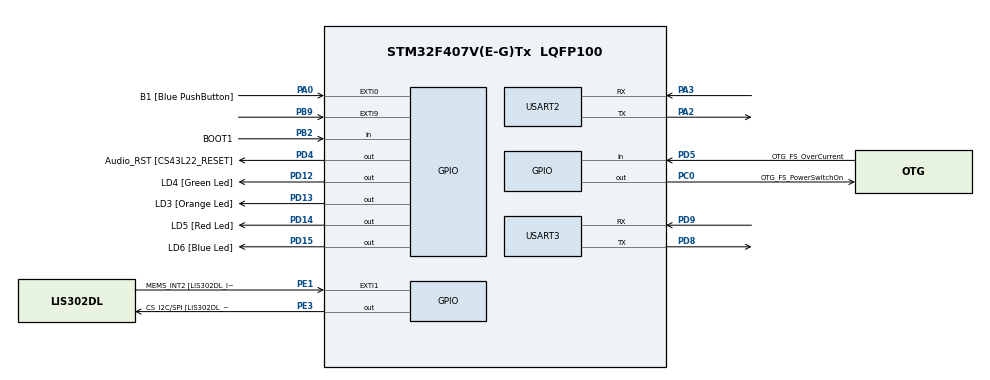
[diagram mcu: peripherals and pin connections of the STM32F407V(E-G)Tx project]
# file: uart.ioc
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Dma.Request0=USART2_RX
Dma.USART2_RX.0.Channel=DMA_CHANNEL_4
Dma.USART2_RX.0.Direction=DMA_PERIPH_TO_MEMORY
Dma.USART2_RX.0.FIFOMode=DMA_FIFOMODE_DISABLE
Dma.USART2_RX.0.FIFOThreshold=DMA_FIFO_THRESHOLD_HALFFULL
Dma.USART2_RX.0.Instance=DMA1_Stream5
Dma.USART2_RX.0.MemBurst=DMA_MBURST_SINGLE
Dma.USART2_RX.0.MemDataAlignment=DMA_MDATAALIGN_BYTE
Dma.USART2_RX.0.MemInc=DMA_MINC_DISABLE
Dma.USART2_RX.0.Mode=DMA_NORMAL
Dma.USART2_RX.0.PeriphBurst=DMA_PBURST_SINGLE
Dma.USART2_RX.0.PeriphDataAlignment=DMA_PDATAALIGN_BYTE
Dma.USART2_RX.0.PeriphInc=DMA_PINC_DISABLE
Dma.USART2_RX.0.Priority=DMA_PRIORITY_LOW
Mcu.Family=STM32F4
Mcu.Name=STM32F407V(E-G)Tx
Mcu.Package=LQFP100
NVIC.DMA1_Stream5_IRQn=true\:0\:0
NVIC.PriorityGroup=NVIC_PRIORITYGROUP_0
NVIC.USART2_IRQn=true\:0\:0
NVIC.USART3_IRQn=true\:0\:0
PA0-WKUP.GPIO_Label=B1 [Blue PushButton]
PA0-WKUP.GPIO_ModeDefaultEXTI=GPIO_MODE_EVT_RISING
PA0-WKUP.GPIO_PuPd=GPIO_NOPULL
PA0-WKUP.Signal=GPXTI0
PA10.GPIO_Label=OTG_FS_ID
PA10.GPIO_Mode=GPIO_MODE_AF_PP
PA10.GPIO_PuPd=GPIO_NOPULL
PA10.GPIO_Speed=GPIO_SPEED_LOW
PA10.Signal=USB_OTG_FS_ID
PA11.GPIO_Label=OTG_FS_DM
PA11.GPIO_Mode=GPIO_MODE_AF_PP
PA11.GPIO_PuPd=GPIO_NOPULL
PA11.GPIO_Speed=GPIO_SPEED_LOW
PA11.Signal=USB_OTG_FS_DM
PA12.GPIO_Label=OTG_FS_DP
PA12.GPIO_Mode=GPIO_MODE_AF_PP
PA12.GPIO_PuPd=GPIO_NOPULL
PA12.GPIO_Speed=GPIO_SPEED_LOW
PA12.Signal=USB_OTG_FS_DP
PA13.GPIO_Label=SWDIO
PA13.Mode=Trace-Asynchronous_SW
PA13.Signal=SYS_JTMS-SWDIO
PA14.GPIO_Label=SWCLK
PA14.Mode=Trace-Asynchronous_SW
PA14.Signal=SYS_JTCK-SWCLK
PA2.Mode=Asynchronous
PA2.Signal=USART2_TX
PA3.Mode=Asynchronous
PA3.Signal=USART2_RX
PA4.GPIO_Label=I2S3_WS [CS43L22_LRCK]
PA4.GPIO_Mode=GPIO_MODE_AF_PP
PA4.GPIO_PuPd=GPIO_NOPULL
PA4.GPIO_Speed=GPIO_SPEED_LOW
PA4.Signal=I2S3_WS
PA5.GPIO_Label=SPI1_SCK [LIS302DL_SCL/SPC]
PA5.GPIO_Mode=GPIO_MODE_AF_PP
PA5.GPIO_PuPd=GPIO_NOPULL
PA5.GPIO_Speed=GPIO_SPEED_LOW
PA5.Signal=SPI1_SCK
PA6.GPIO_Label=SPI1_MISO [LIS302DL_SDO]
PA6.GPIO_Mode=GPIO_MODE_AF_PP
PA6.GPIO_PuPd=GPIO_NOPULL
PA6.GPIO_Speed=GPIO_SPEED_LOW
PA6.Signal=SPI1_MISO
PA7.GPIO_Label=SPI1_MOSI [LIS302DL_SDA/SDI/SDO]
PA7.GPIO_Mode=GPIO_MODE_AF_PP
PA7.GPIO_PuPd=GPIO_NOPULL
PA7.GPIO_Speed=GPIO_SPEED_LOW
PA7.Signal=SPI1_MOSI
PA9.GPIO_Label=VBUS_FS
PA9.GPIO_Mode=GPIO_MODE_INPUT
PA9.GPIO_PuPd=GPIO_NOPULL
PA9.Signal=USB_OTG_FS_VBUS
PB10.GPIO_Label=CLK_IN [MP45DT02_CLK]
PB10.GPIO_Mode=GPIO_MODE_AF_PP
PB10.GPIO_PuPd=GPIO_NOPULL
PB10.GPIO_Speed=GPIO_SPEED_LOW
PB10.Signal=I2S2_CK
PB2.GPIO_Label=BOOT1
PB2.GPIO_Mode=GPIO_MODE_INPUT
PB2.GPIO_PuPd=GPIO_NOPULL
PB2.Signal=GPIO_Input
PB3.GPIO_Label=SWO
PB3.Mode=Trace-Asynchronous_SW
PB3.Signal=SYS_JTDO-SWO
PB6.GPIO_Label=Audio_SCL [CS43L22_SCL]
PB6.GPIO_Mode=GPIO_MODE_AF_OD
PB6.GPIO_PuPd=GPIO_NOPULL
PB6.GPIO_Speed=GPIO_SPEED_LOW
PB6.Signal=I2C1_SCL
PB9.Signal=GPXTI9
PC0.GPIO_Label=OTG_FS_PowerSwitchOn
PC0.GPIO_ModeDefaultOutputPP=GPIO_MODE_OUTPUT_PP
PC0.GPIO_PuPd=GPIO_NOPULL
PC0.GPIO_Speed=GPIO_SPEED_LOW
PC0.Signal=GPIO_Output
PC10.GPIO_Label=I2S3_SCK [CS43L22_SCLK]
PC10.GPIO_Mode=GPIO_MODE_AF_PP
PC10.GPIO_PuPd=GPIO_NOPULL
PC10.GPIO_Speed=GPIO_SPEED_LOW
PC10.Signal=I2S3_CK
PC12.GPIO_Label=I2S3_SD [CS43L22_SDIN]
PC12.GPIO_Mode=GPIO_MODE_AF_PP
PC12.GPIO_PuPd=GPIO_NOPULL
PC12.GPIO_Speed=GPIO_SPEED_LOW
PC12.Signal=I2S3_SD
PC14-OSC32_IN.GPIO_Label=PC14-OSC32_IN
PC14-OSC32_IN.Signal=RCC_OSC32_IN
PC15-OSC32_OUT.GPIO_Label=PC15-OSC32_OUT
PC15-OSC32_OUT.Signal=RCC_OSC32_OUT
PC3.GPIO_Label=PDM_OUT [MP45DT02_DOUT]
PC3.GPIO_Mode=GPIO_MODE_AF_PP
PC3.GPIO_PuPd=GPIO_NOPULL
PC3.GPIO_Speed=GPIO_SPEED_LOW
PC3.Signal=I2S2_SD
PC7.GPIO_Label=I2S3_MCK [CS43L22_MCLK]
PC7.GPIO_Mode=GPIO_MODE_AF_PP
PC7.GPIO_PuPd=GPIO_NOPULL
PC7.GPIO_Speed=GPIO_SPEED_LOW
PC7.Signal=I2S3_MCK
PD12.GPIO_Label=LD4 [Green Led]
PD12.GPIO_ModeDefaultOutputPP=GPIO_MODE_OUTPUT_PP
PD12.GPIO_PuPd=GPIO_NOPULL
PD12.GPIO_Speed=GPIO_SPEED_LOW
PD12.Signal=GPIO_Output
PD13.GPIO_Label=LD3 [Orange Led]
PD13.GPIO_ModeDefaultOutputPP=GPIO_MODE_OUTPUT_PP
PD13.GPIO_PuPd=GPIO_NOPULL
PD13.GPIO_Speed=GPIO_SPEED_LOW
PD13.Signal=GPIO_Output
PD14.GPIO_Label=LD5 [Red Led]
PD14.GPIO_ModeDefaultOutputPP=GPIO_MODE_OUTPUT_PP
PD14.GPIO_PuPd=GPIO_NOPULL
PD14.GPIO_Speed=GPIO_SPEED_LOW
PD14.Signal=GPIO_Output
PD15.GPIO_Label=LD6 [Blue Led]
PD15.GPIO_ModeDefaultOutputPP=GPIO_MODE_OUTPUT_PP
PD15.GPIO_PuPd=GPIO_NOPULL
PD15.GPIO_Speed=GPIO_SPEED_LOW
PD15.Signal=GPIO_Output
PD4.GPIO_Label=Audio_RST [CS43L22_RESET]
PD4.GPIO_ModeDefaultOutputPP=GPIO_MODE_OUTPUT_PP
PD4.GPIO_PuPd=GPIO_NOPULL
PD4.GPIO_Speed=GPIO_SPEED_LOW
PD4.Signal=GPIO_Output
PD5.GPIO_Label=OTG_FS_OverCurrent
PD5.GPIO_Mode=GPIO_MODE_INPUT
PD5.GPIO_PuPd=GPIO_NOPULL
PD5.Signal=GPIO_Input
PD8.Mode=Asynchronous
PD8.Signal=USART3_TX
PD9.Mode=Asynchronous
PD9.Signal=USART3_RX
PE1.GPIO_Label=MEMS_INT2 [LIS302DL_INT2]
PE1.GPIO_ModeDefaultEXTI=GPIO_MODE_EVT_RISING
PE1.GPIO_PuPd=GPIO_NOPULL
PE1.Signal=GPXTI1
PE3.GPIO_Label=CS_I2C/SPI [LIS302DL_CS_I2C/SPI]
PE3.GPIO_ModeDefaultOutputPP=GPIO_MODE_OUTPUT_PP
PE3.GPIO_PuPd=GPIO_NOPULL
PE3.GPIO_Speed=GPIO_SPEED_LOW
PE3.Signal=GPIO_Output
PH0-OSC_IN.GPIO_Label=PH0-OSC_IN
PH0-OSC_IN.Mode=HSE-External-Oscillator
PH0-OSC_IN.Signal=RCC_OSC_IN
PH1-OSC_OUT.GPIO_Label=PH1-OSC_OUT
PH1-OSC_OUT.Mode=HSE-External-Oscillator
PH1-OSC_OUT.Signal=RCC_OSC_OUT
ProjectManager.TargetToolchain=MDK-ARM 4.73
RCC.48MHZClocksFreq_Value=96000000
RCC.AHBFreq_Value=336000000
RCC.APB1CLKDivider=RCC_HCLK_DIV4
RCC.APB1Freq_Value=84000000
RCC.APB1TimFreq_Value=168000000
RCC.APB2CLKDivider=RCC_HCLK_DIV2
RCC.APB2Freq_Value=168000000
RCC.APB2TimFreq_Value=336000000
RCC.ClockTypePCLK1-ClockTree=RCC_CLOCKTYPE_PCLK1
RCC.ClockTypePCLK2-ClockTree=RCC_CLOCKTYPE_PCLK2
RCC.ClockTypeSysClk-ClockTree=RCC_CLOCKTYPE_SYSCLK
RCC.CortexFreq_Value=42000000
RCC.EnableExtClockForI2S-ClockTree=false
RCC.EnableHSE-ClockTree=true
RCC.EnableHSERTCDevisor-ClockTree=false
RCC.EnableLSE-ClockTree=false
RCC.EnableLSERTC-ClockTree=false
RCC.ExtClockEnable-ClockTree=false
RCC.FLatency-AdvancedSettings=FLASH_LATENCY_5
RCC.HCLKFreq_Value=336000000
RCC.HSEState-ClockTree=RCC_HSE_ON
RCC.HSE_VALUE=8000000
RCC.HSIState-ClockTree=RCC_HSI_OFF
RCC.HSI_VALUE=16000000
RCC.I2SEnable-ClockTree=false
RCC.IWDGEnable-ClockTree=false
RCC.LSE_VALUE=32768
RCC.LSIState-ClockTree=RCC_LSI_OFF
RCC.MCO1OutPutEnable-ClockTree=false
RCC.MCO2OutPutEnable-ClockTree=false
RCC.OscillatorTypeHSE-ClockTree=RCC_OSCILLATORTYPE_HSE
RCC.PLLM=8
RCC.PLLN=336
RCC.PLLQ=7
RCC.PLLSource=RCC_PLLSOURCE_HSE
RCC.PLLState-ClockTree=RCC_PLL_ON
RCC.PWR_Regulator_Voltage_Scale-AdvancedSettings=PWR_REGULATOR_VOLTAGE_SCALE1
RCC.RNGEnable-ClockTree=false
RCC.RTCEnable-ClockTree=false
RCC.SDIOEnable-ClockTree=false
RCC.SYSCLKFreq_VALUE=336000000
RCC.SYSCLKSource=RCC_SYSCLKSOURCE_PLLCLK
RCC.USBFSEnable-ClockTree=false
RCC.USBHSEnable-ClockTree=false
RCC.VCOOutputFreq_Value=672000000
TIM6.CounterMode-Enable_Timer=TIM_COUNTERMODE_UP
TIM6.TIM_MasterSlaveMode-Enable_Timer=TIM_MASTERSLAVEMODE_DISABLE
USART2.HwFlowCtl-Asynchronous=UART_HWCONTROL_NONE
USART2.VirtualMode-Asynchronous=VM_ASYNC
USART3.HwFlowCtl-Asynchronous=UART_HWCONTROL_NONE
USART3.VirtualMode-Asynchronous=VM_ASYNC
VP_TIM6_VS_ClockSourceINT.Mode=Enable_Timer

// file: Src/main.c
/**
  ******************************************************************************
  * File Name          : main.c
  * Date               : 03/11/2014 22:31:35
  * Description        : Main program body
  ******************************************************************************
  *
  * COPYRIGHT(c) 2014 STMicroelectronics
  *
  * Redistribution and use in source and binary forms, with or without modification,
  * are permitted provided that the following conditions are met:
  *   1. Redistributions of source code must retain the above copyright notice,
  *      this list of conditions and the following disclaimer.
  *   2. Redistributions in binary form must reproduce the above copyright notice,
  *      this list of conditions and the following disclaimer in the documentation
  *      and/or other materials provided with the distribution.
  *   3. Neither the name of STMicroelectronics nor the names of its contributors
  *      may be used to endorse or promote products derived from this software
  *      without specific prior written permission.
  *
  * THIS SOFTWARE IS PROVIDED BY THE COPYRIGHT HOLDERS AND CONTRIBUTORS "AS IS"
  * AND ANY EXPRESS OR IMPLIED WARRANTIES, INCLUDING, BUT NOT LIMITED TO, THE
  * IMPLIED WARRANTIES OF MERCHANTABILITY AND FITNESS FOR A PARTICULAR PURPOSE ARE
  * DISCLAIMED. IN NO EVENT SHALL THE COPYRIGHT HOLDER OR CONTRIBUTORS BE LIABLE
  * FOR ANY DIRECT, INDIRECT, INCIDENTAL, SPECIAL, EXEMPLARY, OR CONSEQUENTIAL
  * DAMAGES (INCLUDING, BUT NOT LIMITED TO, PROCUREMENT OF SUBSTITUTE GOODS OR
  * SERVICES; LOSS OF USE, DATA, OR PROFITS; OR BUSINESS INTERRUPTION) HOWEVER
  * CAUSED AND ON ANY THEORY OF LIABILITY, WHETHER IN CONTRACT, STRICT LIABILITY,
  * OR TORT (INCLUDING NEGLIGENCE OR OTHERWISE) ARISING IN ANY WAY OUT OF THE USE
  * OF THIS SOFTWARE, EVEN IF ADVISED OF THE POSSIBILITY OF SUCH DAMAGE.
  *
  ******************************************************************************
  */

#include "stm32f4xx_hal.h"

/* USER CODE BEGIN Includes */
#include <string.h>
/* USER CODE END Includes */

TIM_HandleTypeDef htim6;

UART_HandleTypeDef huart2;
UART_HandleTypeDef huart3;
DMA_HandleTypeDef hdma_usart2_rx;

void SystemClock_Config(void);
static void MX_GPIO_Init(void);
static void MX_DMA_Init(void);
static void MX_TIM6_Init(void);
static void MX_USART2_UART_Init(void);
static void MX_USART3_UART_Init(void);

int main(void)
{

  /* MCU Configuration----------------------------------------------------------*/

  /* Reset of all peripherals, Initializes the Flash interface and the Systick. */
  HAL_Init();

  /* Configure the system clock */
  SystemClock_Config();

  /* Initialize all configured peripherals */
  MX_GPIO_Init();
  MX_DMA_Init();
  MX_TIM6_Init();
  MX_USART2_UART_Init();
  MX_USART3_UART_Init();

	const char string[100] = "Hello World!";
	HAL_UART_Transmit(&huart3, (uint8_t)string , strlen(string), 1000);
  while (1)
  {
  }

}

/** System Clock Configuration
*/
void SystemClock_Config(void)
{

  RCC_OscInitTypeDef RCC_OscInitStruct;
  RCC_ClkInitTypeDef RCC_ClkInitStruct;

  __PWR_CLK_ENABLE();

  __HAL_PWR_VOLTAGESCALING_CONFIG(PWR_REGULATOR_VOLTAGE_SCALE1);

  RCC_OscInitStruct.OscillatorType = RCC_OSCILLATORTYPE_HSE;
  RCC_OscInitStruct.HSEState = RCC_HSE_ON;
  RCC_OscInitStruct.PLL.PLLState = RCC_PLL_ON;
  RCC_OscInitStruct.PLL.PLLSource = RCC_PLLSOURCE_HSE;
  RCC_OscInitStruct.PLL.PLLM = 8;
  RCC_OscInitStruct.PLL.PLLN = 336;
  RCC_OscInitStruct.PLL.PLLP = RCC_PLLP_DIV2;
  RCC_OscInitStruct.PLL.PLLQ = 7;
  HAL_RCC_OscConfig(&RCC_OscInitStruct);

  RCC_ClkInitStruct.ClockType = RCC_CLOCKTYPE_SYSCLK|RCC_CLOCKTYPE_PCLK1
                              |RCC_CLOCKTYPE_PCLK2;
  RCC_ClkInitStruct.SYSCLKSource = RCC_SYSCLKSOURCE_PLLCLK;
  RCC_ClkInitStruct.AHBCLKDivider = RCC_SYSCLK_DIV1;
  RCC_ClkInitStruct.APB1CLKDivider = RCC_HCLK_DIV4;
  RCC_ClkInitStruct.APB2CLKDivider = RCC_HCLK_DIV2;
  HAL_RCC_ClockConfig(&RCC_ClkInitStruct, FLASH_LATENCY_5);

}

/* TIM6 init function */
void MX_TIM6_Init(void)
{

  TIM_MasterConfigTypeDef sMasterConfig;

  htim6.Instance = TIM6;
  htim6.Init.Prescaler = 0;
  htim6.Init.CounterMode = TIM_COUNTERMODE_UP;
  htim6.Init.Period = 0;
  HAL_TIM_Base_Init(&htim6);

  sMasterConfig.MasterOutputTrigger = TIM_TRGO_RESET;
  sMasterConfig.MasterSlaveMode = TIM_MASTERSLAVEMODE_DISABLE;
  HAL_TIMEx_MasterConfigSynchronization(&htim6, &sMasterConfig);

}

/* USART2 init function */
void MX_USART2_UART_Init(void)
{

  huart2.Instance = USART2;
  huart2.Init.BaudRate = 115200;
  huart2.Init.WordLength = UART_WORDLENGTH_8B;
  huart2.Init.StopBits = UART_STOPBITS_1;
  huart2.Init.Parity = UART_PARITY_NONE;
  huart2.Init.Mode = UART_MODE_TX_RX;
  huart2.Init.HwFlowCtl = UART_HWCONTROL_NONE;
  huart2.Init.OverSampling = UART_OVERSAMPLING_16;
  HAL_UART_Init(&huart2);

}

/* USART3 init function */
void MX_USART3_UART_Init(void)
{

  huart3.Instance = USART3;
  huart3.Init.BaudRate = 115200;
  huart3.Init.WordLength = UART_WORDLENGTH_8B;
  huart3.Init.StopBits = UART_STOPBITS_1;
  huart3.Init.Parity = UART_PARITY_NONE;
  huart3.Init.Mode = UART_MODE_TX_RX;
  huart3.Init.HwFlowCtl = UART_HWCONTROL_NONE;
  huart3.Init.OverSampling = UART_OVERSAMPLING_16;
  HAL_UART_Init(&huart3);

}

void MX_DMA_Init(void)
{
  /* DMA controller clock enable */
  __DMA1_CLK_ENABLE();

  /* DMA interrupt init */
  HAL_NVIC_SetPriority(DMA1_Stream5_IRQn, 0, 0);
  HAL_NVIC_EnableIRQ(DMA1_Stream5_IRQn);

}

/** Configure pins as
        * Analog
        * Input
        * Output
        * EVENT_OUT
        * EXTI
     PC3   ------> I2S2_SD
     PA4   ------> I2S3_WS
     PA5   ------> SPI1_SCK
     PA6   ------> SPI1_MISO
     PA7   ------> SPI1_MOSI
     PB10   ------> I2S2_CK
     PC7   ------> I2S3_MCK
     PA9   ------> USB_OTG_FS_VBUS
     PA10   ------> USB_OTG_FS_ID
     PA11   ------> USB_OTG_FS_DM
     PA12   ------> USB_OTG_FS_DP
     PC10   ------> I2S3_CK
     PC12   ------> I2S3_SD
     PB6   ------> I2C1_SCL
*/
void MX_GPIO_Init(void)
{

  GPIO_InitTypeDef GPIO_InitStruct;

  /* GPIO Ports Clock Enable */
  __GPIOE_CLK_ENABLE();
  __GPIOC_CLK_ENABLE();
  __GPIOH_CLK_ENABLE();
  __GPIOA_CLK_ENABLE();
  __GPIOB_CLK_ENABLE();
  __GPIOD_CLK_ENABLE();

  /*Configure GPIO pin : PE3 */
  GPIO_InitStruct.Pin = GPIO_PIN_3;
  GPIO_InitStruct.Mode = GPIO_MODE_OUTPUT_PP;
  GPIO_InitStruct.Pull = GPIO_NOPULL;
  GPIO_InitStruct.Speed = GPIO_SPEED_LOW;
  HAL_GPIO_Init(GPIOE, &GPIO_InitStruct);

  /*Configure GPIO pin : PC0 */
  GPIO_InitStruct.Pin = GPIO_PIN_0;
  GPIO_InitStruct.Mode = GPIO_MODE_OUTPUT_PP;
  GPIO_InitStruct.Pull = GPIO_NOPULL;
  GPIO_InitStruct.Speed = GPIO_SPEED_LOW;
  HAL_GPIO_Init(GPIOC, &GPIO_InitStruct);

  /*Configure GPIO pin : PC3 */
  GPIO_InitStruct.Pin = GPIO_PIN_3;
  GPIO_InitStruct.Mode = GPIO_MODE_AF_PP;
  GPIO_InitStruct.Pull = GPIO_NOPULL;
  GPIO_InitStruct.Speed = GPIO_SPEED_LOW;
  GPIO_InitStruct.Alternate = GPIO_AF5_SPI2;
  HAL_GPIO_Init(GPIOC, &GPIO_InitStruct);

  /*Configure GPIO pin : PA0 */
  GPIO_InitStruct.Pin = GPIO_PIN_0;
  GPIO_InitStruct.Mode = GPIO_MODE_EVT_RISING;
  GPIO_InitStruct.Pull = GPIO_NOPULL;
  HAL_GPIO_Init(GPIOA, &GPIO_InitStruct);

  /*Configure GPIO pin : PA4 */
  GPIO_InitStruct.Pin = GPIO_PIN_4;
  GPIO_InitStruct.Mode = GPIO_MODE_AF_PP;
  GPIO_InitStruct.Pull = GPIO_NOPULL;
  GPIO_InitStruct.Speed = GPIO_SPEED_LOW;
  GPIO_InitStruct.Alternate = GPIO_AF6_SPI3;
  HAL_GPIO_Init(GPIOA, &GPIO_InitStruct);

  /*Configure GPIO pins : PA5 PA6 PA7 */
  GPIO_InitStruct.Pin = GPIO_PIN_5|GPIO_PIN_6|GPIO_PIN_7;
  GPIO_InitStruct.Mode = GPIO_MODE_AF_PP;
  GPIO_InitStruct.Pull = GPIO_NOPULL;
  GPIO_InitStruct.Speed = GPIO_SPEED_LOW;
  GPIO_InitStruct.Alternate = GPIO_AF5_SPI1;
  HAL_GPIO_Init(GPIOA, &GPIO_InitStruct);

  /*Configure GPIO pin : PB2 */
  GPIO_InitStruct.Pin = GPIO_PIN_2;
  GPIO_InitStruct.Mode = GPIO_MODE_INPUT;
  GPIO_InitStruct.Pull = GPIO_NOPULL;
  HAL_GPIO_Init(GPIOB, &GPIO_InitStruct);

  /*Configure GPIO pin : PB10 */
  GPIO_InitStruct.Pin = GPIO_PIN_10;
  GPIO_InitStruct.Mode = GPIO_MODE_AF_PP;
  GPIO_InitStruct.Pull = GPIO_NOPULL;
  GPIO_InitStruct.Speed = GPIO_SPEED_LOW;
  GPIO_InitStruct.Alternate = GPIO_AF5_SPI2;
  HAL_GPIO_Init(GPIOB, &GPIO_InitStruct);

  /*Configure GPIO pins : PD12 PD13 PD14 PD15
                           PD4 */
  GPIO_InitStruct.Pin = GPIO_PIN_12|GPIO_PIN_13|GPIO_PIN_14|GPIO_PIN_15
                          |GPIO_PIN_4;
  GPIO_InitStruct.Mode = GPIO_MODE_OUTPUT_PP;
  GPIO_InitStruct.Pull = GPIO_NOPULL;
  GPIO_InitStruct.Speed = GPIO_SPEED_LOW;
  HAL_GPIO_Init(GPIOD, &GPIO_InitStruct);

  /*Configure GPIO pins : PC7 PC10 PC12 */
  GPIO_InitStruct.Pin = GPIO_PIN_7|GPIO_PIN_10|GPIO_PIN_12;
  GPIO_InitStruct.Mode = GPIO_MODE_AF_PP;
  GPIO_InitStruct.Pull = GPIO_NOPULL;
  GPIO_InitStruct.Speed = GPIO_SPEED_LOW;
  GPIO_InitStruct.Alternate = GPIO_AF6_SPI3;
  HAL_GPIO_Init(GPIOC, &GPIO_InitStruct);

  /*Configure GPIO pin : PA9 */
  GPIO_InitStruct.Pin = GPIO_PIN_9;
  GPIO_InitStruct.Mode = GPIO_MODE_INPUT;
  GPIO_InitStruct.Pull = GPIO_NOPULL;
  HAL_GPIO_Init(GPIOA, &GPIO_InitStruct);

  /*Configure GPIO pins : PA10 PA11 PA12 */
  GPIO_InitStruct.Pin = GPIO_PIN_10|GPIO_PIN_11|GPIO_PIN_12;
  GPIO_InitStruct.Mode = GPIO_MODE_AF_PP;
  GPIO_InitStruct.Pull = GPIO_NOPULL;
  GPIO_InitStruct.Speed = GPIO_SPEED_LOW;
  GPIO_InitStruct.Alternate = GPIO_AF10_OTG_FS;
  HAL_GPIO_Init(GPIOA, &GPIO_InitStruct);

  /*Configure GPIO pin : PD5 */
  GPIO_InitStruct.Pin = GPIO_PIN_5;
  GPIO_InitStruct.Mode = GPIO_MODE_INPUT;
  GPIO_InitStruct.Pull = GPIO_NOPULL;
  HAL_GPIO_Init(GPIOD, &GPIO_InitStruct);

  /*Configure GPIO pin : PB6 */
  GPIO_InitStruct.Pin = GPIO_PIN_6;
  GPIO_InitStruct.Mode = GPIO_MODE_AF_OD;
  GPIO_InitStruct.Pull = GPIO_NOPULL;
  GPIO_InitStruct.Speed = GPIO_SPEED_LOW;
  GPIO_InitStruct.Alternate = GPIO_AF4_I2C1;
  HAL_GPIO_Init(GPIOB, &GPIO_InitStruct);

  /*Configure GPIO pin : PB9 */
  GPIO_InitStruct.Pin = GPIO_PIN_9;
  GPIO_InitStruct.Mode = GPIO_MODE_EVT_RISING;
  GPIO_InitStruct.Pull = GPIO_NOPULL;
  HAL_GPIO_Init(GPIOB, &GPIO_InitStruct);

  /*Configure GPIO pin : PE1 */
  GPIO_InitStruct.Pin = GPIO_PIN_1;
  GPIO_InitStruct.Mode = GPIO_MODE_EVT_RISING;
  GPIO_InitStruct.Pull = GPIO_NOPULL;
  HAL_GPIO_Init(GPIOE, &GPIO_InitStruct);

}

/************************ (C) COPYRIGHT STMicroelectronics *****END OF FILE****/
